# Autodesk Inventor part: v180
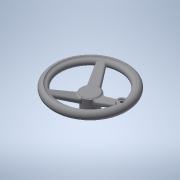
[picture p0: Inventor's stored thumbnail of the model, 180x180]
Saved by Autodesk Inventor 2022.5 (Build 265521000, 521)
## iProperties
Created: 2016-12
Part Number: v180
Material: 一般
Document SubType Name: Modeling
Designer: imaocorp
Density: 1 g/cm^3
Appearance: 既定
Author: imaocorp
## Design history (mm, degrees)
node "v180.x_t1"
node "v180"
node "Base1"
